VERSION 5.7 ;
  NOWIREEXTENSIONATPIN ON ;
  DIVIDERCHAR "/" ;
  BUSBITCHARS "[]" ;
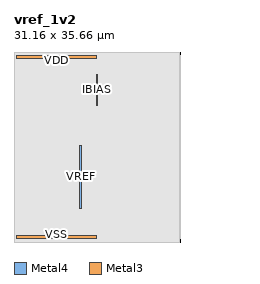
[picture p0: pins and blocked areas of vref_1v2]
MACRO vref_1v2
  CLASS BLOCK ;
  FOREIGN vref_1v2 ;
  ORIGIN 15.580 3.940 ;
  SIZE 31.160 BY 35.660 ;
  PIN IBIAS
    ANTENNAGATEAREA 32.000000 ;
    ANTENNADIFFAREA 1.200000 ;
    PORT
      LAYER Metal4 ;
        RECT -0.140 21.680 0.140 27.520 ;
    END
  END IBIAS
  PIN VREF
    ANTENNAGATEAREA 78.659996 ;
    ANTENNADIFFAREA 8.325000 ;
    PORT
      LAYER Metal4 ;
        RECT -3.200 2.300 -2.920 14.260 ;
    END
  END VREF
  PIN VSS
    USE GROUND ;
    PORT
      LAYER Metal3 ;
        RECT -15.160 -3.220 -0.140 -2.660 ;
    END
  END VSS
  PIN VDD
    USE POWER ;
    PORT
      LAYER Metal3 ;
        RECT -15.160 30.440 -0.140 31.000 ;
    END
  END VDD
  OBS
      LAYER Nwell ;
        RECT -12.360 0.000 12.360 27.680 ;
      LAYER Metal1 ;
        RECT -12.130 0.210 12.130 27.470 ;
      LAYER Metal2 ;
        RECT -12.130 0.210 12.130 27.470 ;
      LAYER Metal3 ;
        RECT -15.580 30.860 -15.160 31.000 ;
        RECT -15.580 30.580 -15.440 30.860 ;
        RECT -15.580 30.440 -15.160 30.580 ;
        RECT -15.580 30.140 -15.460 30.440 ;
        RECT 0.160 30.140 15.580 31.000 ;
        RECT -15.580 -2.360 15.580 30.140 ;
        RECT -15.580 -2.660 -15.460 -2.360 ;
        RECT -15.580 -2.800 -15.160 -2.660 ;
        RECT -15.580 -3.080 -15.440 -2.800 ;
        RECT -15.580 -3.220 -15.160 -3.080 ;
        RECT 0.160 -3.220 15.580 -2.360 ;
      LAYER Metal4 ;
        RECT -15.550 27.820 15.550 30.970 ;
        RECT -15.550 21.380 -0.440 27.820 ;
        RECT 0.440 21.380 15.550 27.820 ;
        RECT -15.550 14.560 15.550 21.380 ;
        RECT -15.550 2.000 -3.500 14.560 ;
        RECT -2.620 2.000 15.550 14.560 ;
        RECT -15.550 -3.190 15.550 2.000 ;
      LAYER Metal5 ;
        RECT -15.550 -3.940 15.550 31.720 ;
  END
END vref_1v2
END LIBRARY

